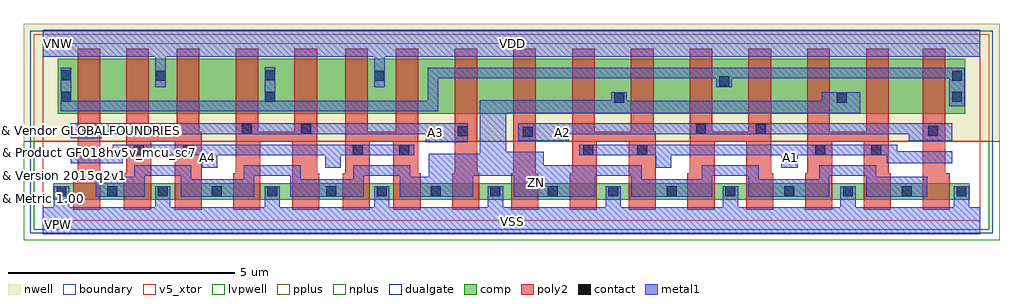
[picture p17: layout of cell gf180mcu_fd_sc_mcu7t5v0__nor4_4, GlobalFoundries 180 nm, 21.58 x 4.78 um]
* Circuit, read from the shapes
.subckt gf180mcu_fd_sc_mcu7t5v0__nor4_4 A1 A2 A3 A4 VDD VNW VSS ZN
XM1 ZN A3 VSS VSUBS nfet_05v0 w=0.36u l=0.6u m=4
XM2 VSS A4 ZN VSUBS nfet_05v0 w=0.36u l=0.6u m=4
XM3 ZN A2 VSS VSUBS nfet_05v0 w=0.36u l=0.6u m=4
XM4 VSS A1 ZN VSUBS nfet_05v0 w=0.36u l=0.6u m=4
XM5 n1 A3 n2 VNW pfet_05v0 w=1.215u l=0.5u
XM6 VDD A4 n1 VNW pfet_05v0 w=1.215u l=0.5u
XM7 n3 A4 VDD VNW pfet_05v0 w=1.215u l=0.5u
XM8 n2 A3 n3 VNW pfet_05v0 w=1.215u l=0.5u
XM9 n4 A3 n2 VNW pfet_05v0 w=1.215u l=0.5u
XM10 VDD A4 n4 VNW pfet_05v0 w=1.215u l=0.5u
XM11 n5 A4 VDD VNW pfet_05v0 w=1.215u l=0.5u
XM12 n6 A3 n5 VNW pfet_05v0 w=1.215u l=0.5u
XM13 n7 A2 n6 VNW pfet_05v0 w=1.215u l=0.5u
XM14 ZN A1 n7 VNW pfet_05v0 w=1.215u l=0.5u
XM15 n8 A1 ZN VNW pfet_05v0 w=1.215u l=0.5u
XM16 n2 A2 n8 VNW pfet_05v0 w=1.215u l=0.5u
XM17 n9 A2 n2 VNW pfet_05v0 w=1.215u l=0.5u
XM18 ZN A1 n9 VNW pfet_05v0 w=1.215u l=0.5u
XM19 n10 A1 ZN VNW pfet_05v0 w=1.215u l=0.5u
XM20 n2 A2 n10 VNW pfet_05v0 w=1.215u l=0.5u
.ends

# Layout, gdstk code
import gdstk
lib = gdstk.Library(unit=1e-6, precision=1e-09)
def R(c, l, rs):  # rectangles x0, y0, x1, y1
    for r in rs: c.add(gdstk.rectangle(r[:2], r[2:], *l))
def A(c, l, x, y, w, h, nx, ny, dx, dy):  # array of equal rectangles
    R(c, l, [(x+i*dx, y+j*dy, x+i*dx+w, y+j*dy+h) for i in range(nx) for j in range(ny)])
def P(c, l, *ps):  # polygons
    for p in ps: c.add(gdstk.Polygon(p, *l))
boundary = (0, 0)
nwell = (21, 0)
comp = (22, 0)
poly2 = (30, 0)
pplus = (31, 0)
nplus = (32, 0)
contact = (33, 0)
metal1 = (34, 0)
dualgate = (55, 0)
v5_xtor = (112, 1)
lvpwell = (204, 0)

gf180mcu_fd_sc_mcu7t5v0_ = lib.new_cell('gf180mcu_fd_sc_mcu7t5v0__nor4_4')
R(gf180mcu_fd_sc_mcu7t5v0_, boundary, [(0,0,20.72,3.92)])
R(gf180mcu_fd_sc_mcu7t5v0_, nwell, [(-0.43,1.76,21.15,4.35)])
R(gf180mcu_fd_sc_mcu7t5v0_, comp, [(0.23,0.465,20.49,0.825), (0.33,2.365,20.39,3.58)])
P(gf180mcu_fd_sc_mcu7t5v0_, poly2, [(0.67,0.245),(0.67,1.045),(0.77,1.045),(0.77,3.8),(1.27,3.8),(1.27,0.245)],
  [(1.79,0.245),(1.79,1.045),(1.84,1.045),(1.84,3.8),(2.34,3.8),(2.34,1.97),(2.96,1.97),(2.96,3.8),(3.46,3.8),(3.46,1.97),(3.51,1.97),(3.51,0.245),(2.91,0.245),(2.91,1.74),(2.39,1.74),(2.39,0.245)],
  [(4.21,0.245),(4.21,1.045),(4.26,1.045),(4.26,3.8),(4.76,3.8),(4.76,1.97),(5.56,1.97),(5.56,3.8),(6.06,3.8),(6.06,1.045),(6.11,1.045),(6.11,0.245),(5.51,0.245),(5.51,1.74),(4.81,1.74),(4.81,0.245)],
  [(6.63,0.245),(6.63,1.045),(6.68,1.045),(6.68,3.8),(7.18,3.8),(7.18,1.97),(7.8,1.97),(7.8,3.8),(8.3,3.8),(8.3,1.045),(8.35,1.045),(8.35,0.245),(7.75,0.245),(7.75,1.74),(7.23,1.74),(7.23,0.245)],
  [(9.05,0.245),(9.05,1.045),(9.1,1.045),(9.1,3.8),(9.6,3.8),(9.6,1.045),(9.65,1.045),(9.65,0.245)],
  [(10.35,0.245),(10.35,1.045),(10.4,1.045),(10.4,3.8),(10.9,3.8),(10.9,1.045),(10.95,1.045),(10.95,0.245)],
  [(11.65,0.245),(11.65,1.045),(11.7,1.045),(11.7,3.8),(12.2,3.8),(12.2,1.97),(13,1.97),(13,3.8),(13.5,3.8),(13.5,1.97),(13.55,1.97),(13.55,0.245),(12.95,0.245),(12.95,1.74),(12.25,1.74),(12.25,0.245)],
  [(14.25,0.245),(14.25,1.045),(14.3,1.045),(14.3,3.8),(14.8,3.8),(14.8,1.97),(15.6,1.97),(15.6,3.8),(16.1,3.8),(16.1,1.045),(16.15,1.045),(16.15,0.245),(15.55,0.245),(15.55,1.74),(14.85,1.74),(14.85,0.245)],
  [(16.85,0.245),(16.85,1.045),(16.9,1.045),(16.9,3.8),(17.4,3.8),(17.4,1.97),(18.2,1.97),(18.2,3.8),(18.7,3.8),(18.7,1.045),(18.75,1.045),(18.75,0.245),(18.15,0.245),(18.15,1.74),(17.45,1.74),(17.45,0.245)],
  [(19.45,0.245),(19.45,3.8),(19.95,3.8),(19.95,1.045),(20.05,1.045),(20.05,0.245)])
R(gf180mcu_fd_sc_mcu7t5v0_, pplus, [(-0.2,1.76,20.92,4.12)])
R(gf180mcu_fd_sc_mcu7t5v0_, nplus, [(-0.2,-0.2,20.92,1.76)])
A(gf180mcu_fd_sc_mcu7t5v0_, contact, 0.3, 0.535, 0.22, 0.22, 3, 1, 1.12, 0)
A(gf180mcu_fd_sc_mcu7t5v0_, contact, 13.79, 0.535, 0.22, 0.22, 5, 1, 1.3, 0)
R(gf180mcu_fd_sc_mcu7t5v0_, contact, [(3.735,0.535,3.955,0.755), (4.96,0.535,5.18,0.755), (6.26,0.535,6.48,0.755), (7.38,0.535,7.6,0.755), (8.58,0.535,8.8,0.755), (9.895,0.535,10.115,0.755), (11.165,0.535,11.385,0.755), (12.5,0.535,12.72,0.755), (20.2,0.535,20.42,0.755), (2.005,1.455,2.225,1.675), (3.105,1.455,3.325,1.675), (6.85,1.455,7.07,1.675), (7.875,1.455,8.095,1.675), (11.945,1.455,12.165,1.675), (13.145,1.455,13.365,1.675), (17.075,1.455,17.295,1.675), (18.31,1.455,18.53,1.675), (10.61,1.855,10.83,2.075), (0.905,1.865,1.125,2.085), (9.17,1.865,9.39,2.085), (19.58,1.875,19.8,2.095), (4.4,1.92,4.62,2.14), (5.71,1.92,5.93,2.14), (14.44,1.92,14.66,2.14), (15.76,1.92,15.98,2.14), (12.63,2.61,12.85,2.83), (17.55,2.61,17.77,2.83), (20.1,2.625,20.32,2.845), (0.4,2.63,0.62,2.85), (4.91,2.63,5.13,2.85), (14.95,2.97,15.17,3.19), (2.49,3.09,2.71,3.31), (7.33,3.09,7.55,3.31), (20.1,3.095,20.32,3.315), (0.4,3.1,0.62,3.32), (4.91,3.1,5.13,3.32)])
P(gf180mcu_fd_sc_mcu7t5v0_, metal1, [(3.51,1.17),(3.51,1.45),(1.76,1.45),(1.76,1.265),(0.61,1.265),(0.61,1.535),(1.54,1.535),(1.54,1.68),(8.21,1.68),(8.21,1.45),(6.585,1.45),(6.585,1.17),(6.24,1.17),(6.24,1.45),(3.85,1.45),(3.85,1.17)],
  [(8.46,1.73),(8.46,1.91),(1.295,1.91),(1.295,1.82),(0.61,1.82),(0.61,2.15),(9.395,2.15),(9.395,1.73)],
  [(1.17,0.53),(1.17,0.975),(2.02,0.975),(2.02,1.22),(3.28,1.22),(3.28,0.92),(4.44,0.92),(4.44,1.22),(5.7,1.22),(5.7,0.92),(6.86,0.92),(6.86,1.22),(8.12,1.22),(8.12,0.975),(8.535,0.975),(8.535,1.48),(9.66,1.48),(9.66,2.665),(12.57,2.665),(12.57,2.84),(12.91,2.84),(12.91,2.655),(17.215,2.655),(17.215,2.835),(18.07,2.835),(18.07,2.38),(10.24,2.38),(10.24,1.52),(11.07,1.52),(11.07,1.22),(13.24,1.22),(13.24,0.92),(14.57,0.92),(14.57,1.22),(15.83,1.22),(15.83,0.92),(17.16,0.92),(17.16,1.22),(18.43,1.22),(18.43,0.975),(19.55,0.975),(19.55,0.53),(18.2,0.53),(18.2,0.99),(17.39,0.99),(17.39,0.53),(15.6,0.53),(15.6,0.99),(14.8,0.99),(14.8,0.53),(13.01,0.53),(13.01,0.99),(12.21,0.99),(12.21,0.53),(10.405,0.53),(10.405,0.99),(9.51,0.99),(9.51,0.53),(7.89,0.53),(7.89,0.99),(7.09,0.99),(7.09,0.53),(5.47,0.53),(5.47,0.99),(4.67,0.99),(4.67,0.53),(3.05,0.53),(3.05,0.99),(2.25,0.99),(2.25,0.53)],
  [(13.545,1.17),(13.545,1.45),(11.855,1.45),(11.855,1.68),(18.89,1.68),(18.89,1.535),(20.11,1.535),(20.11,1.265),(18.66,1.265),(18.66,1.45),(16.685,1.45),(16.685,1.17),(16.325,1.17),(16.325,1.45),(13.89,1.45),(13.89,1.17)],
  [(10.51,1.77),(10.51,2.15),(20.11,2.15),(20.11,1.77),(19.14,1.77),(19.14,1.91),(11.625,1.91),(11.625,1.77)],
  [(0.395,2.415),(0.395,3.38),(0.625,3.38),(0.625,2.65),(4.905,2.65),(4.905,3.39),(5.135,3.39),(5.135,2.65),(8.51,2.65),(8.51,3.385),(20.38,3.385),(20.38,2.53),(20.04,2.53),(20.04,3.15),(15.23,3.15),(15.23,2.945),(14.89,2.945),(14.89,3.15),(8.74,3.15),(8.74,2.415)],
  [(0,-0.3),(0,0.3),(0.24,0.3),(0.24,0.76),(0.58,0.76),(0.58,0.3),(2.48,0.3),(2.48,0.76),(2.82,0.76),(2.82,0.3),(4.9,0.3),(4.9,0.76),(5.24,0.76),(5.24,0.3),(7.32,0.3),(7.32,0.76),(7.66,0.76),(7.66,0.3),(9.835,0.3),(9.835,0.76),(10.175,0.76),(10.175,0.3),(12.44,0.3),(12.44,0.76),(12.78,0.76),(12.78,0.3),(15.03,0.3),(15.03,0.76),(15.37,0.76),(15.37,0.3),(17.63,0.3),(17.63,0.76),(17.97,0.76),(17.97,0.3),(20.14,0.3),(20.14,0.76),(20.48,0.76),(20.48,0.3),(20.72,0.3),(20.72,-0.3)],
  [(2.485,2.95),(2.485,3.62),(0,3.62),(0,4.22),(20.72,4.22),(20.72,3.62),(7.555,3.62),(7.555,2.95),(7.325,2.95),(7.325,3.62),(2.715,3.62),(2.715,2.95)])
R(gf180mcu_fd_sc_mcu7t5v0_, dualgate, [(-0.28,-0.28,21,4.2)])
R(gf180mcu_fd_sc_mcu7t5v0_, v5_xtor, [(0,0,20.72,3.92)])
R(gf180mcu_fd_sc_mcu7t5v0_, lvpwell, [(-0.43,-0.43,21.15,1.76)])
gf180mcu_fd_sc_mcu7t5v0_.add(gdstk.Label('A3', (8.68,1.96), layer=34, texttype=10))
gf180mcu_fd_sc_mcu7t5v0_.add(gdstk.Label('A4', (3.64,1.4), layer=34, texttype=10))
gf180mcu_fd_sc_mcu7t5v0_.add(gdstk.Label('VDD', (10.375,3.915), layer=34, texttype=10))
gf180mcu_fd_sc_mcu7t5v0_.add(gdstk.Label('VSS', (10.375,-0.01), layer=34, texttype=10))
gf180mcu_fd_sc_mcu7t5v0_.add(gdstk.Label('ZN', (10.92,0.84), layer=34, texttype=10))
gf180mcu_fd_sc_mcu7t5v0_.add(gdstk.Label('A1', (16.52,1.4), layer=34, texttype=10))
gf180mcu_fd_sc_mcu7t5v0_.add(gdstk.Label('A2', (11.48,1.96), layer=34, texttype=10))
gf180mcu_fd_sc_mcu7t5v0_.add(gdstk.Label('& Vendor GLOBALFOUNDRIES', (0,2), layer=63, texttype=63))
gf180mcu_fd_sc_mcu7t5v0_.add(gdstk.Label('& Product GF018hv5v_mcu_sc7', (0,1.5), layer=63, texttype=63))
gf180mcu_fd_sc_mcu7t5v0_.add(gdstk.Label('& Version 2015q2v1', (0,1), layer=63, texttype=63))
gf180mcu_fd_sc_mcu7t5v0_.add(gdstk.Label('& Metric 1.00', (0,0.5), layer=63, texttype=63))
gf180mcu_fd_sc_mcu7t5v0_.add(gdstk.Label('VNW', (0.345,3.92), layer=21, texttype=10))
gf180mcu_fd_sc_mcu7t5v0_.add(gdstk.Label('VPW', (0.34,-0.085), layer=204, texttype=10))

lib.write_gds('gf180mcu_fd_sc_mcu7t5v0__nor4_4.gds')
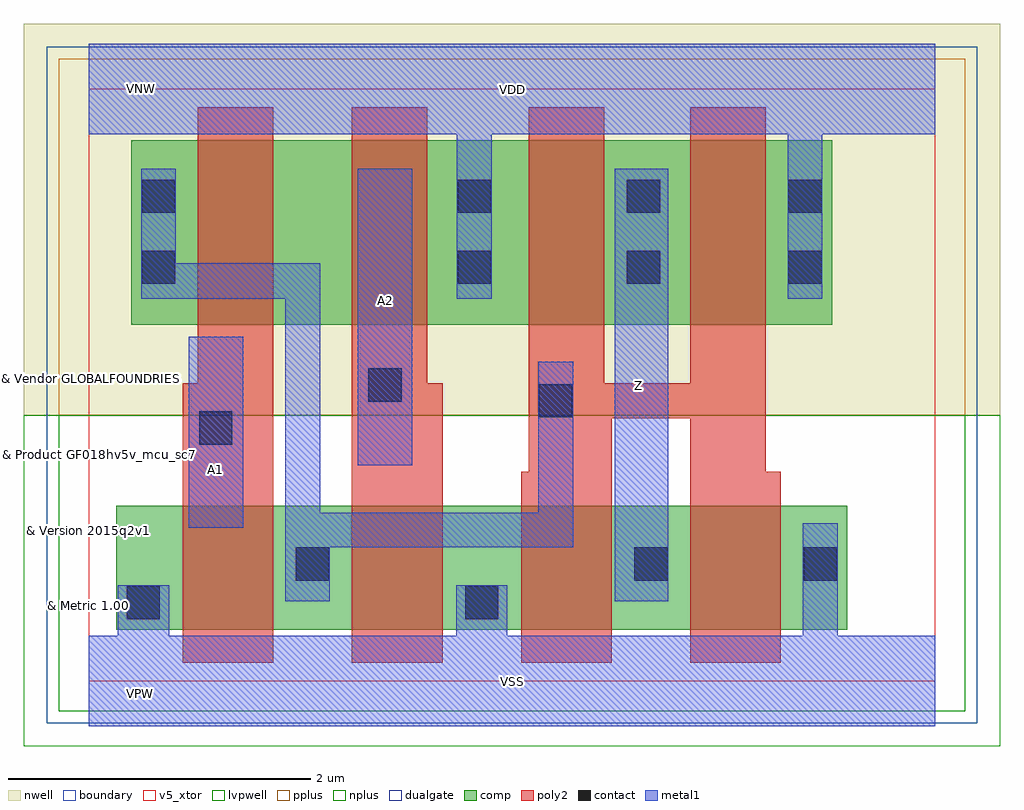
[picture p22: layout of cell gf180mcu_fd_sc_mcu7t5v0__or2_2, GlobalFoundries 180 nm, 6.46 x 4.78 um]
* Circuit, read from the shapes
.subckt gf180mcu_fd_sc_mcu7t5v0__or2_2 A1 A2 VDD VNW VSS Z
XM1 n1 A1 VSS VSUBS nfet_05v0 w=0.82u l=0.6u
XM2 VSS A2 n1 VSUBS nfet_05v0 w=0.82u l=0.6u
XM3 Z n1 VSS VSUBS nfet_05v0 w=0.82u l=0.6u m=2
XM4 n2 A1 n1 VNW pfet_05v0 w=1.22u l=0.5u
XM5 VDD A2 n2 VNW pfet_05v0 w=1.22u l=0.5u
XM6 Z n1 VDD VNW pfet_05v0 w=1.22u l=0.5u m=2
.ends

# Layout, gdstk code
import gdstk
lib = gdstk.Library(unit=1e-6, precision=1e-09)
def R(c, l, rs):  # rectangles x0, y0, x1, y1
    for r in rs: c.add(gdstk.rectangle(r[:2], r[2:], *l))
def P(c, l, *ps):  # polygons
    for p in ps: c.add(gdstk.Polygon(p, *l))
boundary = (0, 0)
nwell = (21, 0)
comp = (22, 0)
poly2 = (30, 0)
pplus = (31, 0)
nplus = (32, 0)
contact = (33, 0)
metal1 = (34, 0)
dualgate = (55, 0)
v5_xtor = (112, 1)
lvpwell = (204, 0)

gf180mcu_fd_sc_mcu7t5v0_ = lib.new_cell('gf180mcu_fd_sc_mcu7t5v0__or2_2')
R(gf180mcu_fd_sc_mcu7t5v0_, boundary, [(0,0,5.6,3.92)])
R(gf180mcu_fd_sc_mcu7t5v0_, nwell, [(-0.43,1.76,6.03,4.35)])
R(gf180mcu_fd_sc_mcu7t5v0_, comp, [(0.18,0.34,5.02,1.16), (0.28,2.36,4.92,3.58)])
P(gf180mcu_fd_sc_mcu7t5v0_, poly2, [(0.62,0.12),(0.62,1.97),(0.72,1.97),(0.72,3.8),(1.22,3.8),(1.22,0.12)],
  [(1.74,0.12),(1.74,3.8),(2.24,3.8),(2.24,1.97),(2.34,1.97),(2.34,0.12)],
  [(2.86,0.12),(2.86,1.385),(2.91,1.385),(2.91,3.8),(3.41,3.8),(3.41,1.97),(3.98,1.97),(3.98,3.8),(4.48,3.8),(4.48,1.385),(4.58,1.385),(4.58,0.12),(3.98,0.12),(3.98,1.74),(3.46,1.74),(3.46,0.12)])
R(gf180mcu_fd_sc_mcu7t5v0_, pplus, [(-0.2,1.76,5.8,4.12)])
R(gf180mcu_fd_sc_mcu7t5v0_, nplus, [(-0.2,-0.2,5.8,1.76)])
R(gf180mcu_fd_sc_mcu7t5v0_, contact, [(0.25,0.41,0.47,0.63), (2.49,0.41,2.71,0.63), (1.37,0.665,1.59,0.885), (3.61,0.665,3.83,0.885), (4.73,0.665,4.95,0.885), (0.73,1.565,0.95,1.785), (2.98,1.745,3.2,1.965), (1.85,1.85,2.07,2.07), (0.35,2.63,0.57,2.85), (2.44,2.63,2.66,2.85), (3.56,2.63,3.78,2.85), (4.63,2.63,4.85,2.85), (0.35,3.1,0.57,3.32), (2.44,3.1,2.66,3.32), (3.56,3.1,3.78,3.32), (4.63,3.1,4.85,3.32)])
R(gf180mcu_fd_sc_mcu7t5v0_, metal1, [(3.48,0.53,3.835,3.39), (0.66,1.015,1.02,2.28), (1.78,1.43,2.14,3.39)])
P(gf180mcu_fd_sc_mcu7t5v0_, metal1, [(1.3,0.53),(1.3,2.53),(0.345,2.53),(0.345,3.39),(0.575,3.39),(0.575,2.765),(1.53,2.765),(1.53,1.115),(2.975,1.115),(2.975,2.115),(3.205,2.115),(3.205,0.885),(1.595,0.885),(1.595,0.53)],
  [(0,-0.3),(0,0.3),(0.19,0.3),(0.19,0.635),(0.53,0.635),(0.53,0.3),(2.43,0.3),(2.43,0.635),(2.77,0.635),(2.77,0.3),(4.725,0.3),(4.725,1.045),(4.955,1.045),(4.955,0.3),(5.6,0.3),(5.6,-0.3)],
  [(2.435,2.53),(2.435,3.62),(0,3.62),(0,4.22),(5.6,4.22),(5.6,3.62),(4.855,3.62),(4.855,2.53),(4.625,2.53),(4.625,3.62),(2.665,3.62),(2.665,2.53)])
R(gf180mcu_fd_sc_mcu7t5v0_, dualgate, [(-0.28,-0.28,5.88,4.2)])
R(gf180mcu_fd_sc_mcu7t5v0_, v5_xtor, [(0,0,5.6,3.92)])
R(gf180mcu_fd_sc_mcu7t5v0_, lvpwell, [(-0.43,-0.43,6.03,1.76)])
gf180mcu_fd_sc_mcu7t5v0_.add(gdstk.Label('VDD', (2.8,3.915), layer=34, texttype=10))
gf180mcu_fd_sc_mcu7t5v0_.add(gdstk.Label('VSS', (2.8,-0.005), layer=34, texttype=10))
gf180mcu_fd_sc_mcu7t5v0_.add(gdstk.Label('Z', (3.64,1.96), layer=34, texttype=10))
gf180mcu_fd_sc_mcu7t5v0_.add(gdstk.Label('A1', (0.84,1.4), layer=34, texttype=10))
gf180mcu_fd_sc_mcu7t5v0_.add(gdstk.Label('A2', (1.96,2.52), layer=34, texttype=10))
gf180mcu_fd_sc_mcu7t5v0_.add(gdstk.Label('& Vendor GLOBALFOUNDRIES', (0,2), layer=63, texttype=63))
gf180mcu_fd_sc_mcu7t5v0_.add(gdstk.Label('& Product GF018hv5v_mcu_sc7', (0,1.5), layer=63, texttype=63))
gf180mcu_fd_sc_mcu7t5v0_.add(gdstk.Label('& Version 2015q2v1', (0,1), layer=63, texttype=63))
gf180mcu_fd_sc_mcu7t5v0_.add(gdstk.Label('& Metric 1.00', (0,0.5), layer=63, texttype=63))
gf180mcu_fd_sc_mcu7t5v0_.add(gdstk.Label('VNW', (0.345,3.92), layer=21, texttype=10))
gf180mcu_fd_sc_mcu7t5v0_.add(gdstk.Label('VPW', (0.34,-0.085), layer=204, texttype=10))

lib.write_gds('gf180mcu_fd_sc_mcu7t5v0__or2_2.gds')
